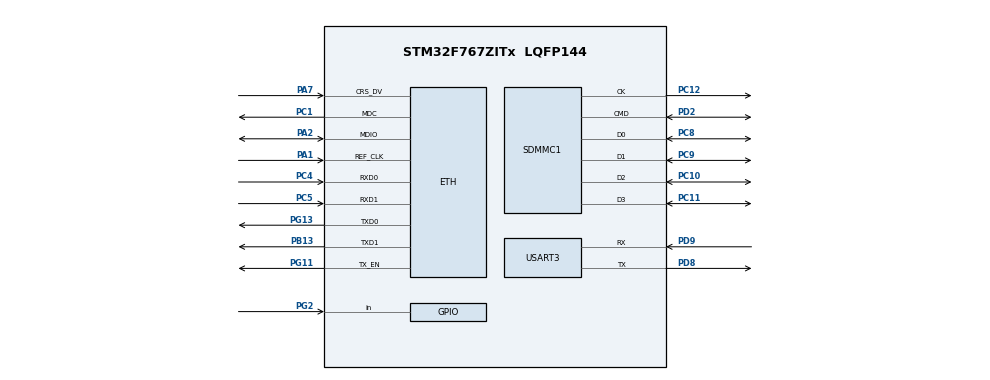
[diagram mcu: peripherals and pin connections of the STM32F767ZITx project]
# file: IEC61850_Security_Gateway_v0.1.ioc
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CORTEX_M7.default_mode_Activation=1
ETH.MediaInterface=HAL_ETH_RMII_MODE
FATFS._USE_LFN=2
FATFS._USE_MUTEX=1
FREERTOS.Queues01=GooseQueue,16,uint32_t,0,Dynamic,NULL,NULL;SCD_StorageQueue,8,uint32_t,0,Dynamic,NULL,NULL;SCD_ConfigQueue,4,uint32_t,0,Dynamic,NULL,NULL;SVQueue,16,uint32_t,0,Dynamic,NULL,NULL;MMSQueue,16,uint32_t,0,Dynamic,NULL,NULL
FREERTOS.Tasks01=defaultTask,0,1024,StartDefaultTask,Default,NULL,Dynamic,NULL,NULL;GooseTask,2,1024,StartGooseTask,Default,NULL,Dynamic,NULL,NULL;SCD_StorageTask,1,512,StartSCD_StorageTask,Default,NULL,Dynamic,NULL,NULL;SCD_ConfigTask,-3,2048,StartSCD_ConfigTask,Default,NULL,Dynamic,NULL,NULL;SVTask,2,1024,StartSVTask,Default,NULL,Dynamic,NULL,NULL;MMSTask,2,1024,StartMMSTask,Default,NULL,Dynamic,NULL,NULL
FREERTOS.configTOTAL_HEAP_SIZE=131072
LWIP.BSP.number=1
LWIP.IP_ADDRESS=169.254.030.019
LWIP.LWIP_DHCP=0
LWIP.LWIP_HTTPD=1
LWIP.LWIP_HTTPD_CUSTOM_FILES=0
LWIP.LWIP_HTTPD_POST_MANUAL_WND=0
LWIP.LWIP_HTTPD_SSI=0
LWIP.LWIP_HTTPD_SSI_MULTIPART=0
LWIP.LWIP_HTTPD_SUPPORT_POST=0
LWIP.LWIP_RAM_HEAP_POINTER=0x20060000
LWIP.LWIP_SMTP=0
LWIP.LWIP_SNTP=0
LWIP.MEM_SIZE=16384
LWIP.NETMASK_ADDRESS=255.255.000.000
LWIP.Version=v2.1.2_Cube
LWIP0.BSP.STBoard=false
LWIP0.BSP.api=BSP_COMPONENT_DRIVER
LWIP0.BSP.component=LAN8742
LWIP0.BSP.instance=LAN8742
LWIP0.BSP.name=Driver_PHY
LWIP0.BSP.semaphore=S_LAN8742
LWIP0.BSP.solution=LAN8742
Mcu.Family=STM32F7
Mcu.Name=STM32F767ZITx
Mcu.Package=LQFP144
NVIC.ETH_IRQn=true\:5\:0\:false\:false\:true\:true\:true\:true\:true
NVIC.PriorityGroup=NVIC_PRIORITYGROUP_4
NVIC.TIM6_DAC_IRQn=true\:15\:0\:false\:false\:true\:false\:false\:true\:true
NVIC.TimeBase=TIM6_DAC_IRQn
NVIC.TimeBaseIP=TIM6
PA1.Mode=RMII
PA1.Signal=ETH_REF_CLK
PA13.Mode=Serial_Wire
PA13.Signal=SYS_JTMS-SWDIO
PA14.Mode=Serial_Wire
PA14.Signal=SYS_JTCK-SWCLK
PA2.Mode=RMII
PA2.Signal=ETH_MDIO
PA7.Mode=RMII
PA7.Signal=ETH_CRS_DV
PB13.Mode=RMII
PB13.Signal=ETH_TXD1
PC1.Mode=RMII
PC1.Signal=ETH_MDC
PC10.GPIO_PuPd=GPIO_PULLUP
PC10.Mode=SD_4_bits_Wide_bus
PC10.Signal=SDMMC1_D2
PC11.GPIO_PuPd=GPIO_PULLUP
PC11.Mode=SD_4_bits_Wide_bus
PC11.Signal=SDMMC1_D3
PC12.GPIO_PuPd=GPIO_PULLUP
PC12.Mode=SD_4_bits_Wide_bus
PC12.Signal=SDMMC1_CK
PC4.Mode=RMII
PC4.Signal=ETH_RXD0
PC5.Mode=RMII
PC5.Signal=ETH_RXD1
PC8.GPIO_PuPd=GPIO_PULLUP
PC8.Mode=SD_4_bits_Wide_bus
PC8.Signal=SDMMC1_D0
PC9.GPIO_PuPd=GPIO_PULLUP
PC9.Mode=SD_4_bits_Wide_bus
PC9.Signal=SDMMC1_D1
PD2.Mode=SD_4_bits_Wide_bus
PD2.Signal=SDMMC1_CMD
PD8.Mode=Asynchronous
PD8.Signal=USART3_TX
PD9.Mode=Asynchronous
PD9.Signal=USART3_RX
PG11.Mode=RMII
PG11.Signal=ETH_TX_EN
PG13.Mode=RMII
PG13.Signal=ETH_TXD0
PG2.GPIO_PuPd=GPIO_PULLUP
PG2.Signal=GPIO_Input
PH0/OSC_IN.Mode=HSE-External-Oscillator
PH0/OSC_IN.Signal=RCC_OSC_IN
PH1/OSC_OUT.Mode=HSE-External-Oscillator
PH1/OSC_OUT.Signal=RCC_OSC_OUT
ProjectManager.HeapSize=0x200
ProjectManager.StackSize=0x400
ProjectManager.TargetToolchain=CMake
RCC.AHBFreq_Value=108000000
RCC.APB1CLKDivider=RCC_HCLK_DIV4
RCC.APB1Freq_Value=27000000
RCC.APB1TimFreq_Value=54000000
RCC.APB2CLKDivider=RCC_HCLK_DIV2
RCC.APB2Freq_Value=54000000
RCC.APB2TimFreq_Value=108000000
RCC.CortexFreq_Value=108000000
RCC.HCLKFreq_Value=108000000
RCC.HSE_VALUE=8000000
RCC.HSI_VALUE=16000000
RCC.LSE_VALUE=32768
RCC.PLLM=8
RCC.PLLN=216
RCC.PLLQ=9
RCC.PLLSourceVirtual=RCC_PLLSOURCE_HSE
RCC.SDMMCClockSelection=RCC_SDMMC1CLKSOURCE_CLK48
RCC.SYSCLKFreq_VALUE=108000000
RCC.SYSCLKSource=RCC_SYSCLKSOURCE_PLLCLK
RCC.USBFreq_Value=24000000
RCC.VCOOutputFreq_Value=216000000
USART3.VirtualMode-Asynchronous=VM_ASYNC
VP_FATFS_VS_Generic.Mode=User_defined
VP_FREERTOS_VS_CMSIS_V1.Mode=CMSIS_V1
VP_LWIP_VS_Enabled.Mode=Enabled
VP_SYS_VS_tim6.Mode=TIM6
board=custom

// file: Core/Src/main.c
/* USER CODE BEGIN Header */
/**
 ******************************************************************************
 * @file           : main.c
 * @brief          : Main program body
 ******************************************************************************
 * @attention
 *
 * Copyright (c) 2026 STMicroelectronics.
 * All rights reserved.
 *
 * This software is licensed under terms that can be found in the LICENSE file
 * in the root directory of this software component.
 * If no LICENSE file comes with this software, it is provided AS-IS.
 *
 ******************************************************************************
 */
/* USER CODE END Header */
#include "main.h"
#include "cmsis_os.h"
#include "fatfs.h"
#include "lwip.h"

/* USER CODE BEGIN Includes */
#include "lwip/apps/httpd.h"
#include "raw_eth.h"
#include "goose.h"
#include "sv.h"
#include "mms.h"
#include "http_api.h"
#include "scd_storage.h"
#include "scd_config.h"
#include "security.h"
#include "sdmmc.h"
#include "system_config.h"
#include "system_logger.h"
#include "storage_service.h"
#include "sys_diag.h"
#include "lwip/tcpip.h"

/* USER CODE END Includes */

SD_HandleTypeDef hsd1;

UART_HandleTypeDef huart3;

osThreadId defaultTaskHandle;
osThreadId GooseTaskHandle;
osThreadId SCD_StorageTaskHandle;
osThreadId SCD_ConfigTaskHandle;
osThreadId SVTaskHandle;
osThreadId MMSTaskHandle;
osMessageQId GooseQueueHandle;
osMessageQId SCD_StorageQueueHandle;
osMessageQId SCD_ConfigQueueHandle;
osMessageQId SVQueueHandle;
osMessageQId MMSQueueHandle;
/* USER CODE BEGIN PV */
extern struct netif gnetif;
extern ETH_HandleTypeDef heth;

/* USER CODE END PV */

void SystemClock_Config(void);
static void MPU_Config(void);
static void MX_GPIO_Init(void);
static void MX_USART3_UART_Init(void);
void MX_SDMMC1_SD_Init(void);
void StartDefaultTask(void const *argument);
void StartGooseTask(void const *argument);
void StartSCD_StorageTask(void const *argument);
void StartSCD_ConfigTask(void const *argument);
void StartSVTask(void const *argument);
void StartMMSTask(void const *argument);

int main(void)
{

  /* USER CODE BEGIN 1 */
  /* Enable Cortex-M7 Instruction Cache for full 216 MHz Flash execution */
  SCB_EnableICache();
  /* USER CODE END 1 */

  /* MPU Configuration--------------------------------------------------------*/
  MPU_Config();

  /* MCU Configuration--------------------------------------------------------*/

  /* Reset of all peripherals, Initializes the Flash interface and the Systick. */
  HAL_Init();

  /* USER CODE BEGIN Init */
  SysDiag_Init();
  /* USER CODE END Init */

  /* Configure the system clock */
  SystemClock_Config();

  /* Initialize all configured peripherals */
  MX_GPIO_Init();
  MX_USART3_UART_Init();
  MX_FATFS_Init();
  MX_SDMMC1_SD_Init();
  /* USER CODE BEGIN 2 */
  f_mount(&USERFatFS, USERPath, 0);
  /* USER CODE END 2 */

  /* Create the queue(s) */
  /* definition and creation of GooseQueue */
  osMessageQDef(GooseQueue, 16, uint32_t);
  GooseQueueHandle = osMessageCreate(osMessageQ(GooseQueue), NULL);

  /* definition and creation of SCD_StorageQueue */
  osMessageQDef(SCD_StorageQueue, 8, uint32_t);
  SCD_StorageQueueHandle = osMessageCreate(osMessageQ(SCD_StorageQueue), NULL);

  /* definition and creation of SCD_ConfigQueue */
  osMessageQDef(SCD_ConfigQueue, 4, uint32_t);
  SCD_ConfigQueueHandle = osMessageCreate(osMessageQ(SCD_ConfigQueue), NULL);

  /* definition and creation of SVQueue */
  osMessageQDef(SVQueue, 32, uint32_t);
  SVQueueHandle = osMessageCreate(osMessageQ(SVQueue), NULL);

  /* definition and creation of MMSQueue */
  osMessageQDef(MMSQueue, 16, uint32_t);
  MMSQueueHandle = osMessageCreate(osMessageQ(MMSQueue), NULL);

  /* Create the thread(s) */
  /* definition and creation of defaultTask */
  osThreadDef(defaultTask, StartDefaultTask, osPriorityNormal, 0, 1024);
  defaultTaskHandle = osThreadCreate(osThread(defaultTask), NULL);

  /* definition and creation of GooseTask */
  osThreadDef(GooseTask, StartGooseTask, osPriorityHigh, 0, 1024);
  GooseTaskHandle = osThreadCreate(osThread(GooseTask), NULL);

  /* definition and creation of SCD_StorageTask */
  osThreadDef(SCD_StorageTask, StartSCD_StorageTask, osPriorityAboveNormal, 0, 1024);
  SCD_StorageTaskHandle = osThreadCreate(osThread(SCD_StorageTask), NULL);

  /* definition and creation of SCD_ConfigTask */
  osThreadDef(SCD_ConfigTask, StartSCD_ConfigTask, osPriorityNormal, 0, 2048);
  SCD_ConfigTaskHandle = osThreadCreate(osThread(SCD_ConfigTask), NULL);

  /* definition and creation of SVTask */
  osThreadDef(SVTask, StartSVTask, osPriorityHigh, 0, 2048);
  SVTaskHandle = osThreadCreate(osThread(SVTask), NULL);

  /* definition and creation of MMSTask */
  osThreadDef(MMSTask, StartMMSTask, osPriorityHigh, 0, 2048);
  MMSTaskHandle = osThreadCreate(osThread(MMSTask), NULL);

  /* USER CODE BEGIN RTOS_THREADS */
  Goose_Init();
  Sv_Init();
  Mms_Init();
  /* USER CODE END RTOS_THREADS */

  /* Start scheduler */
  osKernelStart();

  /* We should never get here as control is now taken by the scheduler */

  /* Infinite loop */
  while (1)
  {

  }
}

void SystemClock_Config(void)
{
  RCC_OscInitTypeDef RCC_OscInitStruct = {0};
  RCC_ClkInitTypeDef RCC_ClkInitStruct = {0};

  /** Configure the main internal regulator output voltage
   */
  __HAL_RCC_PWR_CLK_ENABLE();
  __HAL_PWR_VOLTAGESCALING_CONFIG(PWR_REGULATOR_VOLTAGE_SCALE1);

  /** Initializes the RCC Oscillators according to the specified parameters
   * in the RCC_OscInitTypeDef structure.
   */
  RCC_OscInitStruct.OscillatorType = RCC_OSCILLATORTYPE_HSE;
  RCC_OscInitStruct.HSEState = RCC_HSE_ON;
  RCC_OscInitStruct.PLL.PLLState = RCC_PLL_ON;
  RCC_OscInitStruct.PLL.PLLSource = RCC_PLLSOURCE_HSE;
  RCC_OscInitStruct.PLL.PLLM = 4;
  RCC_OscInitStruct.PLL.PLLN = 216;
  RCC_OscInitStruct.PLL.PLLP = RCC_PLLP_DIV2;
  RCC_OscInitStruct.PLL.PLLQ = 9;
  RCC_OscInitStruct.PLL.PLLR = 2;
  if (HAL_RCC_OscConfig(&RCC_OscInitStruct) != HAL_OK)
  {
    Error_Handler();
  }

  /** Activate the Over-Drive mode
   */
  if (HAL_PWREx_EnableOverDrive() != HAL_OK)
  {
    Error_Handler();
  }

  /** Initializes the CPU, AHB and APB buses clocks
   */
  RCC_ClkInitStruct.ClockType = RCC_CLOCKTYPE_HCLK | RCC_CLOCKTYPE_SYSCLK | RCC_CLOCKTYPE_PCLK1 | RCC_CLOCKTYPE_PCLK2;
  RCC_ClkInitStruct.SYSCLKSource = RCC_SYSCLKSOURCE_PLLCLK;
  RCC_ClkInitStruct.AHBCLKDivider = RCC_SYSCLK_DIV1;
  RCC_ClkInitStruct.APB1CLKDivider = RCC_HCLK_DIV4;
  RCC_ClkInitStruct.APB2CLKDivider = RCC_HCLK_DIV2;

  if (HAL_RCC_ClockConfig(&RCC_ClkInitStruct, FLASH_LATENCY_7) != HAL_OK)
  {
    Error_Handler();
  }
}

void MX_SDMMC1_SD_Init(void)
{

  /* Initialize SDMMC1 GPIOs and peripheral power cleanly using register-level driver */
  SDMMC_GPIO_Init();
}

static void MX_USART3_UART_Init(void)
{

  huart3.Instance = USART3;
  huart3.Init.BaudRate = 115200;
  huart3.Init.WordLength = UART_WORDLENGTH_8B;
  huart3.Init.StopBits = UART_STOPBITS_1;
  huart3.Init.Parity = UART_PARITY_NONE;
  huart3.Init.Mode = UART_MODE_TX_RX;
  huart3.Init.HwFlowCtl = UART_HWCONTROL_NONE;
  huart3.Init.OverSampling = UART_OVERSAMPLING_16;
  huart3.Init.OneBitSampling = UART_ONE_BIT_SAMPLE_DISABLE;
  huart3.AdvancedInit.AdvFeatureInit = UART_ADVFEATURE_NO_INIT;
  if (HAL_UART_Init(&huart3) != HAL_OK)
  {
    Error_Handler();
  }
}

static void MX_GPIO_Init(void)
{
  GPIO_InitTypeDef GPIO_InitStruct = {0};

  /* GPIO Ports Clock Enable */
  __HAL_RCC_GPIOH_CLK_ENABLE();
  __HAL_RCC_GPIOC_CLK_ENABLE();
  __HAL_RCC_GPIOA_CLK_ENABLE();
  __HAL_RCC_GPIOB_CLK_ENABLE();
  __HAL_RCC_GPIOD_CLK_ENABLE();
  __HAL_RCC_GPIOG_CLK_ENABLE();

  /*Configure GPIO pin : PG2 */
  GPIO_InitStruct.Pin = GPIO_PIN_2;
  GPIO_InitStruct.Mode = GPIO_MODE_INPUT;
  GPIO_InitStruct.Pull = GPIO_PULLUP;
  HAL_GPIO_Init(GPIOG, &GPIO_InitStruct);

}

/* USER CODE BEGIN 4 */
int __io_putchar(int ch)
{
  HAL_UART_Transmit(&huart3, (uint8_t *)&ch, 1, HAL_MAX_DELAY);
  return ch;
}

int _write(int file, char *ptr, int len)
{
  (void)file;
  if (ptr == NULL || len <= 0)
  {
    return 0;
  }
  HAL_UART_Transmit(&huart3, (uint8_t *)ptr, (uint16_t)len, 100);
  return len;
}

/* USER CODE END 4 */

void StartDefaultTask(void const *argument)
{
  /* init code for LWIP */
  MX_LWIP_Init();
  /* USER CODE BEGIN 5 */
  SysLog_Init();
  SysLog_Print(SYSLOG_LEVEL_INFO, "BOOT", "IEC 61850 Security Gateway started. STM32F767ZI.");
  SystemConfig_Init();
  SCD_Storage_Init();
  SCD_Config_Init();
  Security_Init();
  StorageService_Init();
  Security_SyncAlertCounter();

  LOCK_TCPIP_CORE();
  HTTP_API_Init();
  httpd_init();
  UNLOCK_TCPIP_CORE();

  SCD_Config_RequestLoadStartup();
  SysLog_Print(SYSLOG_LEVEL_INFO, "SYS", "HTTP server listening on port %d", HTTP_API_PORT);

  for (;;)
  {
    StorageService_Run();
  }
  /* USER CODE END 5 */
}

void StartGooseTask(void const *argument)
{
  /* USER CODE BEGIN StartGooseTask */
  Goose_Task(argument);
  /* USER CODE END StartGooseTask */
}

void StartSCD_StorageTask(void const *argument)
{
  /* USER CODE BEGIN StartSCD_StorageTask */
  SCD_Storage_Task(argument);
  /* USER CODE END StartSCD_StorageTask */
}

void StartSCD_ConfigTask(void const *argument)
{
  /* USER CODE BEGIN StartSCD_ConfigTask */
  SCD_Config_Task(argument);
  /* USER CODE END StartSCD_ConfigTask */
}

void StartSVTask(void const *argument)
{
  /* USER CODE BEGIN StartSVTask */
  Sv_Task(argument);
  /* USER CODE END StartSVTask */
}

void StartMMSTask(void const *argument)
{
  /* USER CODE BEGIN StartMMSTask */
  Mms_Task(argument);
  /* USER CODE END StartMMSTask */
}

/* MPU Configuration */

void MPU_Config(void)
{
  MPU_Region_InitTypeDef MPU_InitStruct = {0};

  /* Disables the MPU */
  HAL_MPU_Disable();

  /** Initializes and configures the Region and the memory to be protected
   */
  MPU_InitStruct.Enable = MPU_REGION_ENABLE;
  MPU_InitStruct.Number = MPU_REGION_NUMBER0;
  MPU_InitStruct.BaseAddress = 0x0;
  MPU_InitStruct.Size = MPU_REGION_SIZE_4GB;
  MPU_InitStruct.SubRegionDisable = 0x87;
  MPU_InitStruct.TypeExtField = MPU_TEX_LEVEL0;
  MPU_InitStruct.AccessPermission = MPU_REGION_NO_ACCESS;
  MPU_InitStruct.DisableExec = MPU_INSTRUCTION_ACCESS_DISABLE;
  MPU_InitStruct.IsShareable = MPU_ACCESS_SHAREABLE;
  MPU_InitStruct.IsCacheable = MPU_ACCESS_NOT_CACHEABLE;
  MPU_InitStruct.IsBufferable = MPU_ACCESS_NOT_BUFFERABLE;

  HAL_MPU_ConfigRegion(&MPU_InitStruct);
  /* Enables the MPU */
  HAL_MPU_Enable(MPU_PRIVILEGED_DEFAULT);
}

void HAL_TIM_PeriodElapsedCallback(TIM_HandleTypeDef *htim)
{
  if (htim->Instance == TIM6)
  {
    HAL_IncTick();
  }
}

void Error_Handler(void)
{
  __disable_irq();
  while (1)
  {
  }
}
